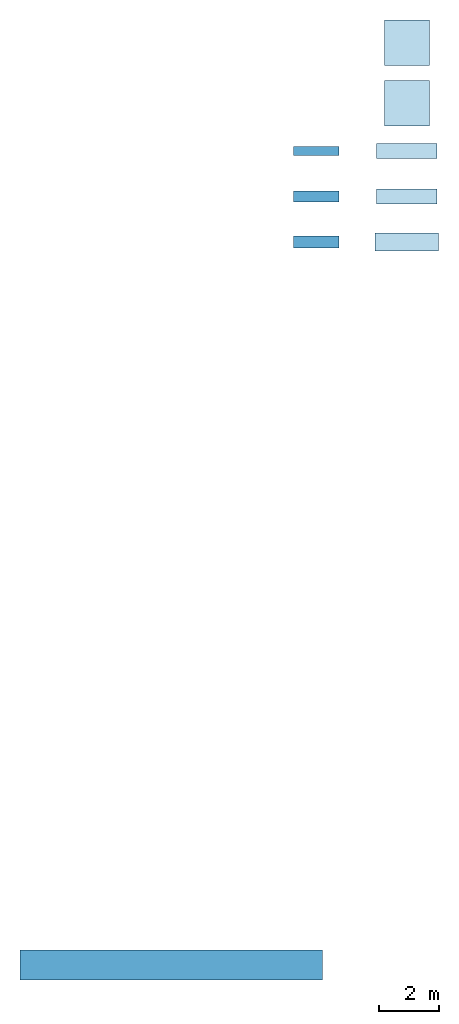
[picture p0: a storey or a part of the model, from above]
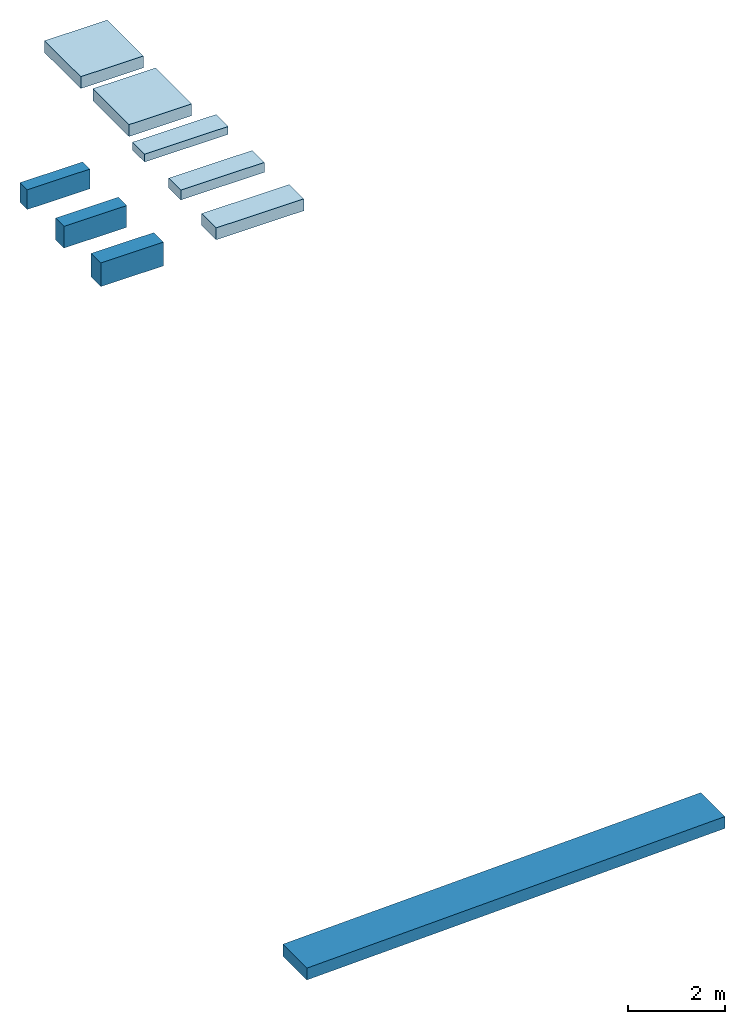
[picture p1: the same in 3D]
Properties of the parts of a building model (IFC2X3)

# File
Description: ViewDefinition [CoordinationView_V2.0]
Time: 2013-09-27T11:32:29
Written by: The EXPRESS Data Manager Version 5.01.0100.02.64mod : 6 Jun 2012
Made in: 20130308_1515(x64) - Exporter 3.5.0.0 - Alternate UI 2.5.0.0
Comment: STEP Physical File produced by: The EXPRESS Data Manager Version 5.01.0100.02.64mod : 6 Jun 2012 * Module: EDMstepFileFactory/EDMstandAlone * Creation date: Fri Sep 27 11:32:29 2013 * Host: MDR_LPTP_BTO * Database: C:\Users\Martijn\AppData\Local\Temp\{5681AB90-63A4-409C-9CCB-B684B3D83B4A}\ifc * Database version: 5507 * Database creation date: Fri Sep 27 11:31:57 2013 * Schema: IFC2X3 * Model: DataRepository.ifc * Model creation date: Fri Sep 27 11:31:58 2013 * Header model: DataRepository.ifc_HeaderModel * Header model creation date: Fri Sep 27 11:31:58 2013 * EDMuser: sdai-user * EDMgroup: sdai-group * License ID and type: 5605 : Permanent license. Expiry date: * EDMstepFileFactory options: 020000

# IfcProject
LongName: E:\MdR Advies\Google Drive\001 - Overige werkzaamheden\RTC\RTC2013 Session 6 - IFC for Interoperability\files\presentation files\example 1 - default export using DRS parameter mapping.ifc

# IfcSite, Surface:5707
RefLatitude: 52, 22, 59, 879998; RefLongitude: 4, 55, 0, 119998; RefElevation: 0 mm

# IfcBuilding
Pset_BuildingCommon - NumberOfStoreys: 8

# IfcBuildingStorey (3)
Name | LongName | Elevation (mm)
-01 kelder | -01 kelder | -3000
00_begane grond | 00_begane grond | 0
01_eerste verdieping | 01_eerste verdieping | 3000

# IfcBuildingElementProxy: 00_Mass_bestaand:229168 : 00_Mass_bestaand:00_Mass_bestaand:229168, 00_Mass_bestaand:00_Mass_bestaand:229168:00_Mass_bestaand:229168 : 00_Mass_bestaand:00_Mass_bestaand:229168:4787
In: 00_begane grond
Material: 000_MA_bestaande bebouwing_IP
Pset_BuildingElementProxyCommon - Reference: 00_Mass_bestaand

# IfcBuildingElementProxy: 45_CEI_plafond_MEP_host:55413 : Basic Ceiling:45_CEI_plafond_MEP_host:55413, Basic Ceiling:45_CEI_plafond_MEP_host:55413:45_CEI_plafond_MEP_host:55413 : Basic Ceiling:45_CEI_plafond_MEP_host:55413:2324
In: 00_begane grond
Pset_BuildingElementProxyCommon - Reference: 45_CEI_plafond_MEP_host

# IfcBuildingElementProxy: 45_CEI_plafond_gipsplaat_610mm_wit:58956 : Compound Ceiling:45_CEI_plafond_gipsplaat_610mm_wit:58956, Compound Ceiling:45_CEI_plafond_gipsplaat_610mm_wit:58956:45_CEI_plafond_gipsplaat_610mm_wit:58956 : Compound Ceiling:45_CEI_plafond_gipsplaat_610mm_wit:58956:2332
In: 00_begane grond
Material: 45_gips_plafond_beplating_610mm
Pset_BuildingElementProxyCommon - Reference: 45_CEI_plafond_gipsplaat_610mm_wit:58956 : Compound Ceiling:45_CEI_plafond_gipsplaat_610mm_wit:58956

# IfcBuildingElementProxy: 45_CEI_systeemplafond_1200x600_wit:59181 : Compound Ceiling:45_CEI_systeemplafond_1200x600_wit:59181, Compound Ceiling:45_CEI_systeemplafond_1200x600_wit:59181:45_CEI_systeemplafond_1200x600_wit:59181 : Compound Ceiling:45_CEI_systeemplafond_1200x600_wit:59181:2381
In: 00_begane grond
Material: 45_plafond_systeemplafond_1200x600_wit
Pset_BuildingElementProxyCommon - Reference: 45_CEI_systeemplafond_1200x600_wit

# IfcBuildingElementProxy: 45_CEI_systeemplafond_600x600_rood:59157 : Compound Ceiling:45_CEI_systeemplafond_600x600_rood:59157, Compound Ceiling:45_CEI_systeemplafond_600x600_rood:59157:45_CEI_systeemplafond_600x600_rood:59157 : Compound Ceiling:45_CEI_systeemplafond_600x600_rood:59157:2366
In: 00_begane grond
Material: 45_plafond_systeemplafond_600x600_donkerrood
Pset_BuildingElementProxyCommon - Reference: 45_CEI_systeemplafond_600x600_rood

# IfcBuildingElementProxy: 45_CEI_systeemplafond_600x600_wit:59123 : Compound Ceiling:45_CEI_systeemplafond_600x600_wit:59123, Compound Ceiling:45_CEI_systeemplafond_600x600_wit:59123:45_CEI_systeemplafond_600x600_wit:59123 : Compound Ceiling:45_CEI_systeemplafond_600x600_wit:59123:2347
In: 00_begane grond
Material: 45_plafond_systeemplafond_600x600_wit
Pset_BuildingElementProxyCommon - Reference: 45_CEI_systeemplafond_600x600_wit

# IfcFlowFitting: 61_CT_kabelgoot_open:180304 : Cable Tray with Fittings:61_CT_kabelgoot_open:180304, Cable Tray with Fittings:61_CT_kabelgoot_open:180304:61_CT_kabelgoot_open:180304 : Cable Tray with Fittings:61_CT_kabelgoot_open:180304:4527
In: 00_begane grond
Pset_DistributionFlowElementCommon - Reference: 61_CT_kabelgoot_open

# IfcFlowFitting: 61_CT_kabelgoot_open:206202 : Cable Tray without Fittings:61_CT_kabelgoot_open:206202, Cable Tray without Fittings:61_CT_kabelgoot_open:206202:61_CT_kabelgoot_open:206202 : Cable Tray without Fittings:61_CT_kabelgoot_open:206202:4714
In: 00_begane grond
Pset_DistributionFlowElementCommon - Reference: 61_CT_kabelgoot_open

# IfcFlowTerminal: aanvoer_plafondrooster_kanaaldiameter_250:221553 : 57_AT_plafondrooster_toev_rond_kanaal_FB:aanvoer_plafondrooster_kanaaldiameter_250:221553, 57_AT_plafondrooster_toev_rond_kanaal_FB:aanvoer_plafondrooster_kanaaldiameter_250:221553:aanvoer_plafondrooster_kanaaldiameter_250:221553 : 57_AT_plafondrooster_toev_rond_kanaal_FB:aanvoer_plafondrooster_kanaaldiameter_250:221553:2163
In: 00_begane grond
Pset_ManufacturerTypeInformation - Manufacturer: RevitGG

# IfcFlowTerminal: afvoer_plafondrooster_kanaaldiameter_250:124771 : 57_AT_plafondrooster_afv_rond_kanaal_FB:afvoer_plafondrooster_kanaaldiameter_250:124771, 57_AT_plafondrooster_afv_rond_kanaal_FB:afvoer_plafondrooster_kanaaldiameter_250:124771:afvoer_plafondrooster_kanaaldiameter_250:124771 : 57_AT_plafondrooster_afv_rond_kanaal_FB:afvoer_plafondrooster_kanaaldiameter_250:124771:2126
In: 00_begane grond
Pset_ManufacturerTypeInformation - Manufacturer: RevitGG

# IfcFlowTerminal: afvoer_rozet_kanaaldiameter_200:148100 : 57_AT_afv_rozet_FB:afvoer_rozet_kanaaldiameter_200:148100, 57_AT_afv_rozet_FB:afvoer_rozet_kanaaldiameter_200:148100:afvoer_rozet_kanaaldiameter_200:148100 : 57_AT_afv_rozet_FB:afvoer_rozet_kanaaldiameter_200:148100:2156
In: 00_begane grond
Pset_ManufacturerTypeInformation - Manufacturer: RevitGG

# IfcFooting: Foundation Slab:16_SFO_funderingsplaat_ihwg_beton_C30/37:68150:Foundation Slab:16_SFO_funderingsplaat_ihwg_beton_C30/37:68150, Foundation Slab:16_SFO_funderingsplaat_ihwg_beton_C30/37:68150:16_SFO_funderingsplaat_ihwg_beton_C30/37:68150 : Foundation Slab:16_SFO_funderingsplaat_ihwg_beton_C30/37:68150:2446
In: -01 kelder
Material: 16_beton_ihwg_C30/35

# IfcFooting: Wall Foundation:16_SFO_ihwg beton_C30-35_500x200:317217:Wall Foundation:16_SFO_ihwg beton_C30-35_500x200:317217, Wall Foundation:16_SFO_ihwg beton_C30-35_500x200:317217:16_SFO_ihwg beton_C30-35_500x200:317217 : Wall Foundation:16_SFO_ihwg beton_C30-35_500x200:317217:2189
In: -01 kelder
Material: 16_beton_ihwg_C30/35

# IfcFooting: Wall Foundation:16_SFO_ihwg beton_C30-35_500x250:317290:Wall Foundation:16_SFO_ihwg beton_C30-35_500x250:317290, Wall Foundation:16_SFO_ihwg beton_C30-35_500x250:317290:16_SFO_ihwg beton_C30-35_500x250:317290 : Wall Foundation:16_SFO_ihwg beton_C30-35_500x250:317290:2204
In: -01 kelder
Material: 16_beton_ihwg_C30/35

# IfcFooting: Wall Foundation:16_SFO_ihwg beton_C30-35_600x300:317374:Wall Foundation:16_SFO_ihwg beton_C30-35_600x300:317374, Wall Foundation:16_SFO_ihwg beton_C30-35_600x300:317374:16_SFO_ihwg beton_C30-35_600x300:317374 : Wall Foundation:16_SFO_ihwg beton_C30-35_600x300:317374:2218
In: -01 kelder
Material: 16_beton_ihwg_C30/35

# IfcFooting: Wall Foundation:16_SFO_prefab beton_C35-45_300x500:317420:Wall Foundation:16_SFO_prefab beton_C35-45_300x500:317420, Wall Foundation:16_SFO_prefab beton_C35-45_300x500:317420:16_SFO_prefab beton_C35-45_300x500:317420 : Wall Foundation:16_SFO_prefab beton_C35-45_300x500:317420:2232
In: -01 kelder
Material: 16_beton_prefab_C35-45

# IfcFooting: Wall Foundation:16_SFO_prefab beton_C35-45_350x550:317423:Wall Foundation:16_SFO_prefab beton_C35-45_350x550:317423, Wall Foundation:16_SFO_prefab beton_C35-45_350x550:317423:16_SFO_prefab beton_C35-45_350x550:317423 : Wall Foundation:16_SFO_prefab beton_C35-45_350x550:317423:2247
In: -01 kelder
Material: 16_beton_prefab_C35-45

# IfcFooting: Wall Foundation:16_SFO_prefab beton_C35-45_400x600:317426:Wall Foundation:16_SFO_prefab beton_C35-45_400x600:317426, Wall Foundation:16_SFO_prefab beton_C35-45_400x600:317426:16_SFO_prefab beton_C35-45_400x600:317426 : Wall Foundation:16_SFO_prefab beton_C35-45_400x600:317426:2261
In: -01 kelder
Material: 16_beton_prefab_C35-45

# IfcRamp: Ramp:24_RA_hellingbaan_beton_prefab_300:77835:1:Ramp:24_RA_hellingbaan_beton_prefab_300:77835:1:4334 (2)
In: -01 kelder
Name (Ramp:24_RA_hellingbaan_beton_prefab_300:77835:1:24_RA_hellingbaan_beton_prefab_300:77835:1 : Ramp:24_RA_hellingbaan_beton_prefab_300:77835:1:...)
4336 | Material: 24_beton_prefab_generiek
4336 | Pset_RampCommon - Reference: 24_RA_hellingbaan_beton_prefab_300:77835:1 : Ramp:24_RA_hellingbaan_beton_prefab_300:77835:1; IsExternal: no

# IfcRamp: Ramp:24_RA_hellingbaan_beton_prefab_solid:79050:1:Ramp:24_RA_hellingbaan_beton_prefab_solid:79050:1:4359 (2)
In: 00_begane grond
Name (Ramp:24_RA_hellingbaan_beton_prefab_solid:79050:1:24_RA_hellingbaan_beton_prefab_solid:79050:1 : Ramp:24_RA_hellingbaan_beton_prefab_solid:79050:1:...)
4361 | Material: 24_beton_prefab_generiek
4361 | Pset_RampCommon - Reference: 24_RA_hellingbaan_beton_prefab_solid:79050:1 : Ramp:24_RA_hellingbaan_beton_prefab_solid:79050:1; IsExternal: no

# IfcRoof: 27_CWP_SAB58KD_945:SAB58KD_945:165322:27_CWP_SAB58KD_945:SAB58KD_945:165322:4384, 27_CWP_SAB58KD_945:SAB58KD_945:165322:SAB58KD_945:165322 : 27_CWP_SAB58KD_945:SAB58KD_945:165322:4386
In: 00_begane grond
Material: Default Roof
Pset_RoofCommon - Reference: 27_CW_SAB58KD_945mm; IsExternal: yes

# IfcRoof: Basic Roof:27_RO_dakplaat_enkelschalig_PIR_135_33-90-12:69928:Basic Roof:27_RO_dakplaat_enkelschalig_PIR_135_33-90-12:69928:4278, Basic Roof:27_RO_dakplaat_enkelschalig_PIR_135_33-90-12:69928:27_RO_dakplaat_enkelschalig_PIR_135_33-90-12:69928 : Basic Roof:27_RO_dakplaat_enkelschalig_PIR_135_33-90-12:69928:4280
In: 00_begane grond
Material: Default Roof
Pset_RoofCommon - Reference: 27_RO_dakplaat_enkelschalig_PIR_135_33-90-12; IsExternal: yes

# IfcRoof: Basic Roof:27_RO_dakplaat_sandwich_PIR_106_20-3-80-3:77055:Basic Roof:27_RO_dakplaat_sandwich_PIR_106_20-3-80-3:77055:4320, Basic Roof:27_RO_dakplaat_sandwich_PIR_106_20-3-80-3:77055:27_RO_dakplaat_sandwich_PIR_106_20-3-80-3:77055 : Basic Roof:27_RO_dakplaat_sandwich_PIR_106_20-3-80-3:77055:4322
In: 00_begane grond
Material: Default Roof
Pset_RoofCommon - Reference: 27_RO_dakplaat_sandwich_PIR_106_20-3-80-3; IsExternal: yes

# IfcRoof: Basic Roof:27_RO_generiek_200:69710:Basic Roof:27_RO_generiek_200:69710:4203, Basic Roof:27_RO_generiek_200:69710:27_RO_generiek_200:69710 : Basic Roof:27_RO_generiek_200:69710:4205
In: 00_begane grond
Material: Default Roof
Pset_RoofCommon - Reference: 27_RO_generiek_200; IsExternal: yes

# IfcRoof: Basic Roof:27_RO_generiek_300:69826:Basic Roof:27_RO_generiek_300:69826:4220, Basic Roof:27_RO_generiek_300:69826:27_RO_generiek_300:69826 : Basic Roof:27_RO_generiek_300:69826:4222
In: 00_begane grond
Material: Default Roof
Pset_RoofCommon - Reference: 27_RO_generiek_300; IsExternal: yes

# IfcRoof: Basic Roof:27_RO_hout_underlayment_189_171-18:69921:Basic Roof:27_RO_hout_underlayment_189_171-18:69921:4264, Basic Roof:27_RO_hout_underlayment_189_171-18:69921:27_RO_hout_underlayment_189_171-18:69921 : Basic Roof:27_RO_hout_underlayment_189_171-18:69921:4266
In: 00_begane grond
Material: Default Roof
Pset_RoofCommon - Reference: 27_RO_hout_underlayment_189_171-18; IsExternal: yes

# IfcRoof: Basic Roof:47_RO_dakpan_grijs_300x300:69939:Basic Roof:47_RO_dakpan_grijs_300x300:69939:4292, Basic Roof:47_RO_dakpan_grijs_300x300:69939:47_RO_dakpan_grijs_300x300:69939 : Basic Roof:47_RO_dakpan_grijs_300x300:69939:4294
In: 00_begane grond
Material: Default Roof
Pset_RoofCommon - Reference: 47_RO_dakpan_grijs_300x300; IsExternal: yes

# IfcRoof: Basic Roof:47_RO_dakpan_rood_300x300:69946:Basic Roof:47_RO_dakpan_rood_300x300:69946:4306, Basic Roof:47_RO_dakpan_rood_300x300:69946:47_RO_dakpan_rood_300x300:69946 : Basic Roof:47_RO_dakpan_rood_300x300:69946:4308
In: 00_begane grond
Material: Default Roof
Pset_RoofCommon - Reference: 47_RO_dakpan_rood_300x300; IsExternal: yes

# IfcRoof: Basic Roof:47_RO_isolatie_EPS_bitumen_102_100-2:69892:Basic Roof:47_RO_isolatie_EPS_bitumen_102_100-2:69892:4250, Basic Roof:47_RO_isolatie_EPS_bitumen_102_100-2:69892:47_RO_isolatie_EPS_bitumen_102_100-2:69892 : Basic Roof:47_RO_isolatie_EPS_bitumen_102_100-2:69892:4252
In: 00_begane grond
Material: Default Roof
Pset_RoofCommon - Reference: 47_RO_isolatie_EPS_bitumen_102_100-2; IsExternal: yes

# IfcRoof: Basic Roof:47_RO_isolatie_PIR_bitumen_82_80-2:69885:Basic Roof:47_RO_isolatie_PIR_bitumen_82_80-2:69885:4234, Basic Roof:47_RO_isolatie_PIR_bitumen_82_80-2:69885:47_RO_isolatie_PIR_bitumen_82_80-2:69885 : Basic Roof:47_RO_isolatie_PIR_bitumen_82_80-2:69885:4236
In: 00_begane grond
Material: Default Roof
Pset_RoofCommon - Reference: 47_RO_isolatie_PIR_bitumen_82_80-2; IsExternal: yes

# IfcSlab: Basic Roof:27_RO_dakplaat_enkelschalig_PIR_135_33-90-12:69928:Basic Roof:27_RO_dakplaat_enkelschalig_PIR_135_33-90-12:69928:4278, Basic Roof:27_RO_dakplaat_enkelschalig_PIR_135_33-90-12:69928:27_RO_dakplaat_enkelschalig_PIR_135_33-90-12:69928 : Basic Roof:27_RO_dakplaat_enkelschalig_PIR_135_33-90-12:69928:4280:1
In: 00_begane grond
PredefinedType: ROOF; Material: Default Roof
Pset_SlabCommon - Reference: 27_RO_dakplaat_enkelschalig_PIR_135_33-90-12:69928 : Basic Roof:27_RO_dakplaat_enkelschalig_PIR_135_33-90-12:69928; IsExternal: yes; LoadBearing: yes; PitchAngle: 0 deg

# IfcSlab: Basic Roof:27_RO_dakplaat_sandwich_PIR_106_20-3-80-3:77055:Basic Roof:27_RO_dakplaat_sandwich_PIR_106_20-3-80-3:77055:4320, Basic Roof:27_RO_dakplaat_sandwich_PIR_106_20-3-80-3:77055:27_RO_dakplaat_sandwich_PIR_106_20-3-80-3:77055 : Basic Roof:27_RO_dakplaat_sandwich_PIR_106_20-3-80-3:77055:4322:1
In: 00_begane grond
PredefinedType: ROOF; Material: Default Roof
Pset_SlabCommon - Reference: 27_RO_dakplaat_sandwich_PIR_106_20-3-80-3:77055 : Basic Roof:27_RO_dakplaat_sandwich_PIR_106_20-3-80-3:77055; IsExternal: yes; LoadBearing: yes; PitchAngle: 0 deg

# IfcSlab: Basic Roof:27_RO_generiek_200:69710:Basic Roof:27_RO_generiek_200:69710:4203, Basic Roof:27_RO_generiek_200:69710:27_RO_generiek_200:69710 : Basic Roof:27_RO_generiek_200:69710:4205:1
In: 00_begane grond
PredefinedType: ROOF; Material: Default Roof
Pset_SlabCommon - Reference: 27_RO_generiek_200:69710 : Basic Roof:27_RO_generiek_200:69710; IsExternal: yes; LoadBearing: yes; PitchAngle: 0 deg

# IfcSlab: Basic Roof:27_RO_generiek_300:69826:Basic Roof:27_RO_generiek_300:69826:4220, Basic Roof:27_RO_generiek_300:69826:27_RO_generiek_300:69826 : Basic Roof:27_RO_generiek_300:69826:4222:1
In: 00_begane grond
PredefinedType: ROOF; Material: Default Roof
Pset_SlabCommon - Reference: 27_RO_generiek_300:69826 : Basic Roof:27_RO_generiek_300:69826; IsExternal: yes; LoadBearing: yes; PitchAngle: 0 deg

# IfcSlab: Basic Roof:27_RO_hout_underlayment_189_171-18:69921:Basic Roof:27_RO_hout_underlayment_189_171-18:69921:4264, Basic Roof:27_RO_hout_underlayment_189_171-18:69921:27_RO_hout_underlayment_189_171-18:69921 : Basic Roof:27_RO_hout_underlayment_189_171-18:69921:4266:1
In: 00_begane grond
PredefinedType: ROOF; Material: Default Roof
Pset_SlabCommon - Reference: 27_RO_hout_underlayment_189_171-18:69921 : Basic Roof:27_RO_hout_underlayment_189_171-18:69921; IsExternal: yes; LoadBearing: yes; PitchAngle: 0 deg

# IfcSlab: Basic Roof:47_RO_dakpan_grijs_300x300:69939:Basic Roof:47_RO_dakpan_grijs_300x300:69939:4292, Basic Roof:47_RO_dakpan_grijs_300x300:69939:47_RO_dakpan_grijs_300x300:69939 : Basic Roof:47_RO_dakpan_grijs_300x300:69939:4294:1
In: 00_begane grond
PredefinedType: ROOF; Material: Default Roof
Pset_SlabCommon - Reference: 47_RO_dakpan_grijs_300x300:69939 : Basic Roof:47_RO_dakpan_grijs_300x300:69939; IsExternal: yes; LoadBearing: yes; PitchAngle: 0 deg

# IfcSlab: Basic Roof:47_RO_dakpan_rood_300x300:69946:Basic Roof:47_RO_dakpan_rood_300x300:69946:4306, Basic Roof:47_RO_dakpan_rood_300x300:69946:47_RO_dakpan_rood_300x300:69946 : Basic Roof:47_RO_dakpan_rood_300x300:69946:4308:1
In: 00_begane grond
PredefinedType: ROOF; Material: Default Roof
Pset_SlabCommon - Reference: 47_RO_dakpan_rood_300x300:69946 : Basic Roof:47_RO_dakpan_rood_300x300:69946; IsExternal: yes; LoadBearing: yes; PitchAngle: 0 deg

# IfcSlab: Basic Roof:47_RO_isolatie_EPS_bitumen_102_100-2:69892:Basic Roof:47_RO_isolatie_EPS_bitumen_102_100-2:69892:4250, Basic Roof:47_RO_isolatie_EPS_bitumen_102_100-2:69892:47_RO_isolatie_EPS_bitumen_102_100-2:69892 : Basic Roof:47_RO_isolatie_EPS_bitumen_102_100-2:69892:4252:1
In: 00_begane grond
PredefinedType: ROOF; Material: Default Roof
Pset_SlabCommon - Reference: 47_RO_isolatie_EPS_bitumen_102_100-2:69892 : Basic Roof:47_RO_isolatie_EPS_bitumen_102_100-2:69892; IsExternal: yes; LoadBearing: yes; PitchAngle: 0 deg

# IfcSlab: Basic Roof:47_RO_isolatie_PIR_bitumen_82_80-2:69885:Basic Roof:47_RO_isolatie_PIR_bitumen_82_80-2:69885:4234, Basic Roof:47_RO_isolatie_PIR_bitumen_82_80-2:69885:47_RO_isolatie_PIR_bitumen_82_80-2:69885 : Basic Roof:47_RO_isolatie_PIR_bitumen_82_80-2:69885:4236:1
In: 00_begane grond
PredefinedType: ROOF; Material: Default Roof
Pset_SlabCommon - Reference: 47_RO_isolatie_PIR_bitumen_82_80-2:69885 : Basic Roof:47_RO_isolatie_PIR_bitumen_82_80-2:69885; IsExternal: yes; LoadBearing: yes; PitchAngle: 0 deg

# IfcSlab: Floor:Floor:11_FL_werkvloer_stampbeton_50, Floor:Floor:11_FL_werkvloer_stampbeton_50:5945
In: 00_begane grond
PredefinedType: FLOOR; Material: 11_werkvloer_stampbeton 50 mm
Pset_SlabCommon - Reference: Floor:11_FL_werkvloer_stampbeton_50; IsExternal: yes; LoadBearing: no; FireRating: 30; Combustible: yes; Compartmentation: yes; PitchAngle: 0 deg

# IfcSlab: Floor:Floor:13_FL_generiek_100, Floor:Floor:13_FL_generiek_100:5911
In: 00_begane grond
PredefinedType: FLOOR; Material: Default 100 mm
Pset_SlabCommon - Reference: Floor:13_FL_generiek_100; IsExternal: yes; LoadBearing: no; FireRating: 60; Combustible: no; Compartmentation: yes; PitchAngle: 0 deg

# IfcSlab: Floor:Floor:13_FL_ihwg_beton_geïsoleerd_222_120-100-2, Floor:Floor:13_FL_ihwg_beton_geïsoleerd_222_120-100-2:5953
In: 00_begane grond
PredefinedType: FLOOR; Material: 13_beton_ihwg_C20/25 120 mm, 20_isolatie_EPS 100 mm, 11_bodemafsluiter_folie 2 mm
Pset_SlabCommon - Reference: Floor:13_FL_ihwg_beton_geïsoleerd_222_120-100-2; IsExternal: yes; LoadBearing: no; FireRating: 60; Combustible: no; Compartmentation: yes; PitchAngle: 0 deg

# IfcSlab: Floor:Floor:23_FL_breedplaat_50, Floor:Floor:23_FL_breedplaat_50:5977
In: 00_begane grond
PredefinedType: FLOOR; Material: layer 50 mm
Pset_SlabCommon - Reference: Floor:23_FL_breedplaat_50; IsExternal: no; LoadBearing: no; FireRating: 90; Combustible: no; Compartmentation: yes; PitchAngle: 0 deg

# IfcSlab: Floor:Floor:23_FL_breedplaat_60, Floor:Floor:23_FL_breedplaat_60:5985
In: 00_begane grond
PredefinedType: FLOOR; Material: layer 60 mm
Pset_SlabCommon - Reference: Floor:23_FL_breedplaat_60; IsExternal: no; LoadBearing: no; Combustible: yes; Compartmentation: no; PitchAngle: 0 deg

# IfcSlab: Floor:Floor:23_FL_generiek_100, Floor:Floor:23_FL_generiek_100:5928
In: 00_begane grond
PredefinedType: FLOOR; Material: Default 100 mm
Pset_SlabCommon - Reference: Floor:23_FL_generiek_100; IsExternal: yes; LoadBearing: no; Combustible: no; Compartmentation: no; PitchAngle: 0 deg

# IfcSlab: Floor:Floor:23_FL_generiek_300, Floor:Floor:23_FL_generiek_300:5936
In: 00_begane grond
PredefinedType: FLOOR; Material: Default 300 mm
Pset_SlabCommon - Reference: Floor:23_FL_generiek_300; IsExternal: yes; LoadBearing: no; Combustible: no; Compartmentation: no; PitchAngle: 0 deg

# IfcSlab: Floor:Floor:23_FL_hout_underlayment_189mm_171-18, Floor:Floor:23_FL_hout_underlayment_189mm_171-18:6026
In: 00_begane grond
PredefinedType: FLOOR; Material: 23_beplating_underlayment 18 mm, 23_houten_balklaag_geventileerd 171 mm
Pset_SlabCommon - Reference: Floor:23_FL_hout_underlayment_189mm_171-18; IsExternal: no; LoadBearing: no; Combustible: no; Compartmentation: no; PitchAngle: 0 deg

# IfcSlab: Floor:Floor:23_FL_ihwg_beton_200, Floor:Floor:23_FL_ihwg_beton_200:5961
In: 00_begane grond
PredefinedType: FLOOR; Material: 13_beton_ihwg_C20/25 200 mm
Pset_SlabCommon - Reference: Floor:23_FL_ihwg_beton_200; IsExternal: no; LoadBearing: no; Combustible: no; Compartmentation: no; PitchAngle: 0 deg

# IfcSlab: Floor:Floor:23_FL_ihwg_beton_300, Floor:Floor:23_FL_ihwg_beton_300:5969
In: 00_begane grond
PredefinedType: FLOOR; Material: 13_beton_ihwg_C20/25 300 mm
Pset_SlabCommon - Reference: Floor:23_FL_ihwg_beton_300; IsExternal: no; LoadBearing: no; FireRating: 90; Combustible: no; Compartmentation: yes; PitchAngle: 0 deg

# IfcSlab: Floor:Floor:23_FL_kanaalplaat_200, Floor:Floor:23_FL_kanaalplaat_200:5993
In: 00_begane grond
PredefinedType: FLOOR; Material: layer 200 mm
Pset_SlabCommon - Reference: Floor:23_FL_kanaalplaat_200; IsExternal: no; LoadBearing: no; Combustible: no; Compartmentation: no; PitchAngle: 0 deg

# IfcSlab: Floor:Floor:23_FL_kanaalplaat_260, Floor:Floor:23_FL_kanaalplaat_260:6001
In: 00_begane grond
PredefinedType: FLOOR; Material: layer 260 mm
Pset_SlabCommon - Reference: Floor:23_FL_kanaalplaat_260; IsExternal: no; LoadBearing: no; Combustible: yes; Compartmentation: no; PitchAngle: 0 deg

# IfcSlab: Floor:Floor:23_FL_zwaluwstaartvloer_ihwg_beton_50, Floor:Floor:23_FL_zwaluwstaartvloer_ihwg_beton_50:6009
In: 00_begane grond
PredefinedType: FLOOR; Material: 13_beton_ihwg_C20/25 50 mm
Pset_SlabCommon - Reference: Floor:23_FL_zwaluwstaartvloer_ihwg_beton_50; IsExternal: no; LoadBearing: no; Combustible: no; Compartmentation: no; PitchAngle: 0 deg

# IfcSlab: Floor:Floor:23_FL_zwaluwstaartvloer_ihwg_beton_75, Floor:Floor:23_FL_zwaluwstaartvloer_ihwg_beton_75:6017
In: 00_begane grond
PredefinedType: FLOOR; Material: 13_beton_ihwg_C20/25 75 mm
Pset_SlabCommon - Reference: Floor:23_FL_zwaluwstaartvloer_ihwg_beton_75; IsExternal: no; LoadBearing: no; Combustible: no; Compartmentation: no; PitchAngle: 0 deg

# IfcSlab: Floor:Floor:43_FL_cementdekvloer_50, Floor:Floor:43_FL_cementdekvloer_50:6034
In: 00_begane grond
PredefinedType: FLOOR; Material: 43_dekvloer_zandcement 50 mm
Pset_SlabCommon - Reference: Floor:43_FL_cementdekvloer_50; IsExternal: no; LoadBearing: no; Combustible: no; Compartmentation: no; PitchAngle: 0 deg

# IfcSlab: Floor:Floor:43_FL_cementdekvloer_70, Floor:Floor:43_FL_cementdekvloer_70:6042
In: 00_begane grond
PredefinedType: FLOOR; Material: 43_dekvloer_zandcement 70 mm
Pset_SlabCommon - Reference: Floor:43_FL_cementdekvloer_70; IsExternal: no; LoadBearing: no; Combustible: no; Compartmentation: no; PitchAngle: 0 deg

# IfcSlab: Floor:Floor:43_FL_eiken_planken 150_geluidsisolatie_52_22-30, Floor:Floor:43_FL_eiken_planken 150_geluidsisolatie_52_22-30:6051
In: 00_begane grond
PredefinedType: FLOOR; Material: 43_vloerafwerking_hout_planken 22 mm, 20_isolatie_steenwol 30 mm
Pset_SlabCommon - Reference: Floor:43_FL_eiken_planken 150_geluidsisolatie_52_22-30; IsExternal: no; LoadBearing: no; Combustible: no; Compartmentation: no; PitchAngle: 0 deg

# IfcSlab: Floor:Floor:43_FL_tapijt_rood, Floor:Floor:43_FL_tapijt_rood:6059
In: 00_begane grond
PredefinedType: FLOOR; Material: 43_tapijt_rood 9 mm
Pset_SlabCommon - Reference: Floor:43_FL_tapijt_rood; IsExternal: no; LoadBearing: no; Combustible: no; Compartmentation: no; PitchAngle: 0 deg

# IfcSlab: Floor:Pad:90_SITE_bouwplaats, Floor:Pad:90_SITE_bouwplaats:6081
In: 00_begane grond
PredefinedType: FLOOR; Material: 90_bouwplaats 300 mm
Pset_SlabCommon - Reference: Pad:90_SITE_bouwplaats; IsExternal: no; LoadBearing: no; PitchAngle: 0 deg

# IfcStair: Assembled Stair:Stair:68679 Run 1:Assembled Stair:Stair:68679 Run 1:2493 (2)
In: 00_begane grond
Name (Assembled Stair:Stair:68679 Run 1:Stair:68679 Run 1 : Assembled Stair:Stair:68679 Run 1:...)
2495
2495 | Pset_StairCommon - Reference: 24_STR_trede_hout_vuren_40_neus_50_stootbord_10; IsExternal: no; NumberOfTreads: 16; TreadLength: 67056 mm

# IfcStair: Assembled Stair:Stair:68679 Stringer 1:Assembled Stair:Stair:68679 Stringer 1:2458 (2)
In: 00_begane grond
Name (Assembled Stair:Stair:68679 Stringer 1:Stair:68679 Stringer 1 : Assembled Stair:Stair:68679 Stringer 1:...)
2460
2460 | Pset_StairCommon - Reference: 24_ST_houten trap_gesloten_b=850_op=185_aan=220; IsExternal: no; NumberOfTreads: 0

# IfcStair: Assembled Stair:Stair:68953 Run 1:Assembled Stair:Stair:68953 Run 1:2779 (2)
In: 00_begane grond
Name (Assembled Stair:Stair:68953 Run 1:Stair:68953 Run 1 : Assembled Stair:Stair:68953 Run 1:...)
2781
2781 | Pset_StairCommon - Reference: 24_STR_trede_hout_vuren_40_neus_50; IsExternal: no; NumberOfTreads: 16; TreadLength: 20438669 mm

# IfcStair: Assembled Stair:Stair:68953 Stringer 1:Assembled Stair:Stair:68953 Stringer 1:2754 (2)
In: 00_begane grond
Name (Assembled Stair:Stair:68953 Stringer 1:Stair:68953 Stringer 1 : Assembled Stair:Stair:68953 Stringer 1:...)
2756
2756 | Pset_StairCommon - Reference: 24_ST_houten trap_open_b=850_op=185_aan=220; IsExternal: no; NumberOfTreads: 0

# IfcStair: Assembled Stair:Stair:69257 Run 1:Assembled Stair:Stair:69257 Run 1:2987 (2)
In: 00_begane grond
Name (Assembled Stair:Stair:69257 Run 1:Stair:69257 Run 1 : Assembled Stair:Stair:69257 Run 1:...)
2989
2989 | Pset_StairCommon - Reference: 24_STR_trede_hout_vuren_40_neus_50; IsExternal: no; NumberOfTreads: 16; TreadLength: 20438669 mm

# IfcStair: Assembled Stair:Stair:69257 Stringer 1:Assembled Stair:Stair:69257 Stringer 1:2902 (2)
In: 00_begane grond
Name (Assembled Stair:Stair:69257 Stringer 1:Stair:69257 Stringer 1 : Assembled Stair:Stair:69257 Stringer 1:...)
2904
2904 | Pset_StairCommon - Reference: 24_ST_houten trap_open_gezadeld_b=850_op=185_aan=220; IsExternal: no; NumberOfTreads: 0

# IfcStair: Assembled Stair:Stair:69261 Run 1:Assembled Stair:Stair:69261 Run 1:3155 (2)
In: 00_begane grond
Name (Assembled Stair:Stair:69261 Run 1:Stair:69261 Run 1 : Assembled Stair:Stair:69261 Run 1:...)
3157
3157 | Pset_StairCommon - Reference: 24_STR_trede_hout_vuren_40_neus_50; IsExternal: no; NumberOfTreads: 16; TreadLength: 20438669 mm

# IfcStair: Assembled Stair:Stair:69261 Stringer 1:Assembled Stair:Stair:69261 Stringer 1:3110 (2)
In: 00_begane grond
Name (Assembled Stair:Stair:69261 Stringer 1:Stair:69261 Stringer 1 : Assembled Stair:Stair:69261 Stringer 1:...)
3112
3112 | Pset_StairCommon - Reference: 24_ST_houten trap_open_middenboom_b=850_op=185_aan=220; IsExternal: no; NumberOfTreads: 0

# IfcStair: Assembled Stair:Stair:69280 Run 1:Assembled Stair:Stair:69280 Run 1:3303 (2)
In: 00_begane grond
Name (Assembled Stair:Stair:69280 Run 1:Stair:69280 Run 1 : Assembled Stair:Stair:69280 Run 1:...)
3305 | Material: 24_staal_gegalvaniseerd_rooster_generiek
3305 | Pset_StairCommon - Reference: 24_STR_trede_staal_gegalvaniseerd_rooster_15_neus_50_stootbord_15; IsExternal: no; NumberOfTreads: 16; TreadLength: 20438669 mm

# IfcStair: Assembled Stair:Stair:69280 Stringer 1:Assembled Stair:Stair:69280 Stringer 1:3278 (2)
In: 00_begane grond
Name (Assembled Stair:Stair:69280 Stringer 1:Stair:69280 Stringer 1 : Assembled Stair:Stair:69280 Stringer 1:...)
3280
3280 | Pset_StairCommon - Reference: 24_ST_stalen trap_gesloten_b=1000_op=185_aan=220; IsExternal: no; NumberOfTreads: 0

# IfcStair: Assembled Stair:Stair:69283 Run 1:Assembled Stair:Stair:69283 Run 1:3571 (2)
In: 00_begane grond
Name (Assembled Stair:Stair:69283 Run 1:Stair:69283 Run 1 : Assembled Stair:Stair:69283 Run 1:...)
3573 | Material: 24_staal_gegalvaniseerd_rooster_generiek
3573 | Pset_StairCommon - Reference: 24_STR_trede_staal_gegalvaniseerd_rooster_15_neus_50; IsExternal: no; NumberOfTreads: 16; TreadLength: 20438669 mm

# IfcStair: Assembled Stair:Stair:69283 Stringer 1:Assembled Stair:Stair:69283 Stringer 1:3546 (2)
In: 00_begane grond
Name (Assembled Stair:Stair:69283 Stringer 1:Stair:69283 Stringer 1 : Assembled Stair:Stair:69283 Stringer 1:...)
3548
3548 | Pset_StairCommon - Reference: 24_ST_stalen trap_open_b=850_op=185_aan=150; IsExternal: no; NumberOfTreads: 0

# IfcStair: Assembled Stair:Stair:69288 Run 1:Assembled Stair:Stair:69288 Run 1:3719 (2)
In: 00_begane grond
Name (Assembled Stair:Stair:69288 Run 1:Stair:69288 Run 1 : Assembled Stair:Stair:69288 Run 1:...)
3721 | Material: 24_staal_gegalvaniseerd_rooster_generiek
3721 | Pset_StairCommon - Reference: 24_STR_trede_staal_gegalvaniseerd_rooster_15_neus_50; IsExternal: no; NumberOfTreads: 16; TreadLength: 20438669 mm

# IfcStair: Assembled Stair:Stair:69288 Stringer 1:Assembled Stair:Stair:69288 Stringer 1:3694 (2)
In: 00_begane grond
Name (Assembled Stair:Stair:69288 Stringer 1:Stair:69288 Stringer 1 : Assembled Stair:Stair:69288 Stringer 1:...)
3696
3696 | Pset_StairCommon - Reference: 24_ST_stalen trap_open_b=850_op=185_aan=220; IsExternal: no; NumberOfTreads: 0

# IfcStair: Assembled Stair:Stair:69305 Run 1:Assembled Stair:Stair:69305 Run 1:3867 (2)
In: 00_begane grond
Name (Assembled Stair:Stair:69305 Run 1:Stair:69305 Run 1 : Assembled Stair:Stair:69305 Run 1:...)
3869 | Material: 24_staal_gegalvaniseerd_rooster_generiek
3869 | Pset_StairCommon - Reference: 24_STR_trede_staal_gegalvaniseerd_rooster_15_neus_50; IsExternal: no; NumberOfTreads: 16; TreadLength: 20438669 mm

# IfcStair: Assembled Stair:Stair:69305 Stringer 1:Assembled Stair:Stair:69305 Stringer 1:3842 (2)
In: 00_begane grond
Name (Assembled Stair:Stair:69305 Stringer 1:Stair:69305 Stringer 1 : Assembled Stair:Stair:69305 Stringer 1:...)
3844
3844 | Pset_StairCommon - Reference: 24_ST_stalen trap_open_b=1000_op=185_aan=350; IsExternal: no; NumberOfTreads: 0

# IfcStair: Assembled Stair:Stair:69309 Run 1:Assembled Stair:Stair:69309 Run 1:4035 (2)
In: 00_begane grond
Name (Assembled Stair:Stair:69309 Run 1:Stair:69309 Run 1 : Assembled Stair:Stair:69309 Run 1:...)
4037 | Material: 24_staal_gegalvaniseerd_rooster_generiek
4037 | Pset_StairCommon - Reference: 24_STR_trede_staal_gegalvaniseerd_rooster_15_neus_50; IsExternal: no; NumberOfTreads: 16; TreadLength: 20438669 mm

# IfcStair: Assembled Stair:Stair:69309 Stringer 1:Assembled Stair:Stair:69309 Stringer 1:3990 (2)
In: 00_begane grond
Name (Assembled Stair:Stair:69309 Stringer 1:Stair:69309 Stringer 1 : Assembled Stair:Stair:69309 Stringer 1:...)
3992
3992 | Pset_StairCommon - Reference: 24_ST_stalen trap_open_middenboom_b=1000_op=185_aan=220; IsExternal: no; NumberOfTreads: 0

# IfcStair: Cast-In-Place Stair:Stair:69314 Run 1:Cast-In-Place Stair:Stair:69314 Run 1:4158 (2)
In: 00_begane grond
Name (Cast-In-Place Stair:Stair:69314 Run 1:Stair:69314 Run 1 : Cast-In-Place Stair:Stair:69314 Run 1:...)
4160 | Material: 24_beton_prefab_generiek
4160 | Pset_StairCommon - Reference: 24_STR_trap_beton_prefab_50_50_50; IsExternal: no; NumberOfTreads: 16; TreadLength: 20438669 mm

# IfcStair: Cast-In-Place Stair:Stair:69318 Run 1:Cast-In-Place Stair:Stair:69318 Run 1:4170 (2)
In: 00_begane grond
Name (Cast-In-Place Stair:Stair:69318 Run 1:Stair:69318 Run 1 : Cast-In-Place Stair:Stair:69318 Run 1:...)
4172 | Material: 24_beton_prefab_generiek
4172 | Pset_StairCommon - Reference: 24_STR_trap_beton_prefab_monolithisch_recht; IsExternal: no; NumberOfTreads: 16; TreadLength: 20438669 mm

# IfcStair: Precast Stair:Stair:69323 Run 1:Precast Stair:Stair:69323 Run 1:4181 (2)
In: 00_begane grond
Name (Precast Stair:Stair:69323 Run 1:Stair:69323 Run 1 : Precast Stair:Stair:69323 Run 1:...)
4183 | Material: 24_beton_prefab_generiek
4183 | Pset_StairCommon - Reference: 24_STR_trap_beton_prefab_monolithisch_recht; IsExternal: no; NumberOfTreads: 16; TreadLength: 20438669 mm

# IfcStair: Precast Stair:Stair:69326 Run 1:Precast Stair:Stair:69326 Run 1:4192 (2)
In: 00_begane grond
Name (Precast Stair:Stair:69326 Run 1:Stair:69326 Run 1 : Precast Stair:Stair:69326 Run 1:...)
4194 | Material: 24_beton_prefab_generiek
4194 | Pset_StairCommon - Reference: 24_STR_trap_beton_prefab_50_50_50; IsExternal: no; NumberOfTreads: 16; TreadLength: 20438669 mm

# IfcWall: Curtain Wall:21_CW_binnendoos_SAB90_500:160824:21_CW_binnendoos_SAB90_500:160824 : Curtain Wall:21_CW_binnendoos_SAB90_500:160824, Curtain Wall:21_CW_binnendoos_SAB90_500:160824:21_CW_binnendoos_SAB90_500:160824 : Curtain Wall:21_CW_binnendoos_SAB90_500:160824:6090
In: 00_begane grond
Pset_WallCommon - Reference: 21_CW_binnendoos_SAB90_500:160824 : Curtain Wall:21_CW_binnendoos_SAB90_500:160824; LoadBearing: no; ExtendToStructure: no; IsExternal: no

# IfcWall: Curtain Wall:21_CW_gevelbeplating_SAB35_1035:60482:21_CW_gevelbeplating_SAB35_1035:60482 : Curtain Wall:21_CW_gevelbeplating_SAB35_1035:60482, Curtain Wall:21_CW_gevelbeplating_SAB35_1035:60482:21_CW_gevelbeplating_SAB35_1035:60482 : Curtain Wall:21_CW_gevelbeplating_SAB35_1035:60482:5924
In: 00_begane grond
Pset_WallCommon - Reference: 21_CW_gevelbeplating_SAB35_1035:60482 : Curtain Wall:21_CW_gevelbeplating_SAB35_1035:60482; LoadBearing: no; ExtendToStructure: no; IsExternal: no

# IfcWallStandardCase: Basic Wall:Basic Wall:20_WA_wand_generiek_100 (7)
In: 00_begane grond
Type - PredefinedType: STANDARD; Material: Default 100 mm
Pset_WallCommon - Reference: Basic Wall:20_WA_wand_generiek_100; LoadBearing: no; ExtendToStructure: no; IsExternal: yes; Combustible: yes; Compartmentation: no
PSet_COBIE - NominalWidth: 100
Name (Basic Wall:Basic Wall:20_WA_wand_generiek_100:...) | NominalLength
5875 | 2000
6094 | 1500
6095 | 1500
6096 | 1500
6097 | 1500
6098 | 1500
6099 | 1500

# IfcWallStandardCase: Basic Wall:Basic Wall:20_WA_wand_generiek_200, Basic Wall:Basic Wall:20_WA_wand_generiek_200:5876
In: 00_begane grond
Type - PredefinedType: STANDARD; Material: Default 200 mm
Pset_WallCommon - Reference: Basic Wall:20_WA_wand_generiek_200; LoadBearing: yes; ExtendToStructure: no; IsExternal: yes; Combustible: no; Compartmentation: no
PSet_COBIE - NominalLength: 2000; NominalWidth: 200

# IfcWallStandardCase: Basic Wall:Basic Wall:20_WA_wand_generiek_300, Basic Wall:Basic Wall:20_WA_wand_generiek_300:5877
In: 00_begane grond
Type - PredefinedType: STANDARD; Material: Default 300 mm
Pset_WallCommon - Reference: Basic Wall:20_WA_wand_generiek_300; LoadBearing: yes; ExtendToStructure: no; IsExternal: yes; Combustible: no; Compartmentation: no
PSet_COBIE - NominalLength: 2000; NominalWidth: 300

# IfcWallStandardCase: Basic Wall:Basic Wall:21_WA_hout-wrc-hor_rachel_tengel_iso-sw_180_20-30-10-120, Basic Wall:Basic Wall:21_WA_hout-wrc-hor_rachel_tengel_iso-sw_180_20-30-10-120:5888
In: 00_begane grond
Type - PredefinedType: STANDARD; Material: 41_hout_hardhout_geveldelen_donkerblauw_horizontaal 20 mm, 40_regelwerk_geventileerd 30 mm, 40_regelwerk_geventileerd 10 mm, 20_isolatie_steenwol 120 mm
Pset_WallCommon - Reference: Basic Wall:21_WA_hout-wrc-hor_rachel_tengel_iso-sw_180_20-30-10-120; LoadBearing: no; ExtendToStructure: no; IsExternal: yes; ThermalTransmittance: 0.274174 kg/K/s3; Combustible: no; Compartmentation: no
PSet_COBIE - NominalLength: 2000; NominalWidth: 180

# IfcWallStandardCase: Basic Wall:Basic Wall:21_WA_mw-bestaand_100, Basic Wall:Basic Wall:21_WA_mw-bestaand_100:5881
In: 00_begane grond
Type - PredefinedType: STANDARD; Material: 00_baksteen_bestaand 100 mm
Pset_WallCommon - Reference: Basic Wall:21_WA_mw-bestaand_100; LoadBearing: no; ExtendToStructure: no; IsExternal: yes; ThermalTransmittance: 4.1 kg/K/s3; Combustible: no; Compartmentation: no
PSet_COBIE - NominalLength: 2000; NominalWidth: 100

# IfcWallStandardCase: Basic Wall:Basic Wall:21_WA_mw-bestaand_spouw_mw-bestaand_300_100-100-100, Basic Wall:Basic Wall:21_WA_mw-bestaand_spouw_mw-bestaand_300_100-100-100:5883
In: 00_begane grond
Type - PredefinedType: STANDARD; Material: 00_baksteen_bestaand 100 mm, 00_lucht_spouw_muur_geventileerd 100 mm, 00_baksteen_bestaand 100 mm
Pset_WallCommon - Reference: Basic Wall:21_WA_mw-bestaand_spouw_mw-bestaand_300_100-100-100; LoadBearing: yes; ExtendToStructure: no; IsExternal: yes; ThermalTransmittance: 1.98096 kg/K/s3; Combustible: no; Compartmentation: no
PSet_COBIE - NominalLength: 2000; NominalWidth: 300

# IfcWallStandardCase: Basic Wall:Basic Wall:21_WA_mw_100, Basic Wall:Basic Wall:21_WA_mw_100:5878
In: 00_begane grond
Type - PredefinedType: STANDARD; Material: 20_baksteen_wf_210x100x50_10mm_voeg_halfsteens_rood_genuanceerd 100 mm
Pset_WallCommon - Reference: Basic Wall:21_WA_mw_100; LoadBearing: no; ExtendToStructure: no; IsExternal: yes; ThermalTransmittance: 4.1 kg/K/s3; Combustible: no; Compartmentation: no
PSet_COBIE - NominalLength: 2000; NominalWidth: 100

# IfcWallStandardCase: Basic Wall:Basic Wall:21_WA_mw_210, Basic Wall:Basic Wall:21_WA_mw_210:5879
In: 00_begane grond
Type - PredefinedType: STANDARD; Material: 20_baksteen_wf_210x100x50_10mm_voeg_halfsteens_rood_genuanceerd 210 mm
Pset_WallCommon - Reference: Basic Wall:21_WA_mw_210; LoadBearing: yes; ExtendToStructure: no; IsExternal: yes; ThermalTransmittance: 1.95238 kg/K/s3; Combustible: no; Compartmentation: no
PSet_COBIE - NominalLength: 2000; NominalWidth: 210

# IfcWallStandardCase: Basic Wall:Basic Wall:21_WA_mw_bestaand_210, Basic Wall:Basic Wall:21_WA_mw_bestaand_210:5882
In: 00_begane grond
Type - PredefinedType: STANDARD; Material: 00_baksteen_bestaand 210 mm
Pset_WallCommon - Reference: Basic Wall:21_WA_mw_bestaand_210; LoadBearing: yes; ExtendToStructure: no; IsExternal: yes; ThermalTransmittance: 1.95238 kg/K/s3; Combustible: no; Compartmentation: no
PSet_COBIE - NominalLength: 2000; NominalWidth: 210

# IfcWallStandardCase: Basic Wall:Basic Wall:21_WA_mw_spouw_170_100-70, Basic Wall:Basic Wall:21_WA_mw_spouw_170_100-70:5884
In: 00_begane grond
Type - PredefinedType: STANDARD; Material: 20_baksteen_wf_210x100x50_10mm_voeg_halfsteens_rood_genuanceerd 100 mm, 00_lucht_spouw_muur_geventileerd 70 mm
Pset_WallCommon - Reference: Basic Wall:21_WA_mw_spouw_170_100-70; LoadBearing: no; ExtendToStructure: no; IsExternal: yes; ThermalTransmittance: 3.90927 kg/K/s3; Combustible: no; Compartmentation: no
PSet_COBIE - NominalLength: 2000; NominalWidth: 170

# IfcWallStandardCase: Basic Wall:Basic Wall:21_WA_mw_spouw_iso-sw_170_100-20-50, Basic Wall:Basic Wall:21_WA_mw_spouw_iso-sw_170_100-20-50:5885
In: 00_begane grond
Type - PredefinedType: STANDARD; Material: 20_baksteen_wf_210x100x50_10mm_voeg_halfsteens_rood_genuanceerd 100 mm, 00_lucht_spouw_muur_geventileerd 20 mm, 20_isolatie_steenwol 50 mm
Pset_WallCommon - Reference: Basic Wall:21_WA_mw_spouw_iso-sw_170_100-20-50; LoadBearing: no; ExtendToStructure: no; IsExternal: yes; ThermalTransmittance: 0.582109 kg/K/s3; Combustible: no; Compartmentation: no
PSet_COBIE - NominalLength: 2000; NominalWidth: 170

# IfcWallStandardCase: Basic Wall:Basic Wall:21_WA_mw_spouw_iso-sw_200_100-30-70 (2)
In: 00_begane grond
Type - PredefinedType: STANDARD; Material: 20_baksteen_wf_210x100x50_10mm_voeg_halfsteens_rood_genuanceerd 100 mm, 00_lucht_spouw_muur_geventileerd 30 mm, 20_isolatie_steenwol 70 mm
Pset_WallCommon - Reference: Basic Wall:21_WA_mw_spouw_iso-sw_200_100-30-70; LoadBearing: no; ExtendToStructure: no; IsExternal: yes; ThermalTransmittance: 0.433308 kg/K/s3; Combustible: no; Compartmentation: no
PSet_COBIE - NominalLength: 2000; NominalWidth: 200
Name (Basic Wall:Basic Wall:21_WA_mw_spouw_iso-sw_200_100-30-70:...)
5886
5887

# IfcWallStandardCase: Basic Wall:Basic Wall:21_WA_mw_spouw_mw_300_100-100-100, Basic Wall:Basic Wall:21_WA_mw_spouw_mw_300_100-100-100:5880
In: 00_begane grond
Type - PredefinedType: STANDARD; Material: 20_baksteen_wf_210x100x50_10mm_voeg_halfsteens_rood_genuanceerd 100 mm, 00_lucht_spouw_muur_geventileerd 100 mm, 20_baksteen_wf_210x100x50_10mm_voeg_halfsteens_rood_genuanceerd 100 mm
Pset_WallCommon - Reference: Basic Wall:21_WA_mw_spouw_mw_300_100-100-100; LoadBearing: yes; ExtendToStructure: no; IsExternal: yes; ThermalTransmittance: 1.98096 kg/K/s3; Combustible: no; Compartmentation: no
PSet_COBIE - NominalLength: 2000; NominalWidth: 300

# IfcWallStandardCase: Basic Wall:Basic Wall:21_WA_sandwichpaneel_100x1000, Basic Wall:Basic Wall:21_WA_sandwichpaneel_100x1000:5891
In: 00_begane grond
Type - PredefinedType: STANDARD; Material: 41_staal_geanodizeerd_wit 1.6 mm, 20_isolatie_PIR 96.8 mm, 41_staal_geanodizeerd_wit 1.6 mm
Pset_WallCommon - Reference: Basic Wall:21_WA_sandwichpaneel_100x1000; LoadBearing: no; ExtendToStructure: no; IsExternal: yes; ThermalTransmittance: 0.309911 kg/K/s3; Combustible: no; Compartmentation: no
PSet_COBIE - NominalLength: 2000; NominalWidth: 100

# IfcWallStandardCase: Basic Wall:Basic Wall:21_WA_spouw_iso-sw_140_40-100, Basic Wall:Basic Wall:21_WA_spouw_iso-sw_140_40-100:6091
In: 00_begane grond
Type - PredefinedType: STANDARD; Material: 00_lucht_spouw_muur_geventileerd 40 mm, 20_isolatie_steenwol 100 mm
Pset_WallCommon - Reference: Basic Wall:21_WA_spouw_iso-sw_140_40-100; LoadBearing: no; ExtendToStructure: no; IsExternal: yes; ThermalTransmittance: 0.339216 kg/K/s3; Combustible: no; Compartmentation: no
PSet_COBIE - NominalLength: 2000; NominalWidth: 140

# IfcWallStandardCase: Basic Wall:Basic Wall:21_WA_stucwerk_iso-eps_150_30-120, Basic Wall:Basic Wall:21_WA_stucwerk_iso-eps_150_30-120:5890
In: 00_begane grond
Type - PredefinedType: STANDARD; Material: 40_stucwerk_exterieur_grof_wit 30 mm, 20_isolatie_EPS 120 mm
Pset_WallCommon - Reference: Basic Wall:21_WA_stucwerk_iso-eps_150_30-120; LoadBearing: no; ExtendToStructure: no; IsExternal: yes; ThermalTransmittance: 0.286747 kg/K/s3; Combustible: no; Compartmentation: no
PSet_COBIE - NominalLength: 2000; NominalWidth: 150

# IfcWallStandardCase: Basic Wall:Basic Wall:22_WA_cb_G2/400_100, Basic Wall:Basic Wall:22_WA_cb_G2/400_100:5898
In: 00_begane grond
Type - PredefinedType: STANDARD; Material: 22_cellenbeton G2/400 100 mm
Pset_WallCommon - Reference: Basic Wall:22_WA_cb_G2/400_100; LoadBearing: no; ExtendToStructure: no; IsExternal: no; ThermalTransmittance: 1.2 kg/K/s3; Combustible: no; Compartmentation: no
PSet_COBIE - NominalLength: 2000; NominalWidth: 100

# IfcWallStandardCase: Basic Wall:Basic Wall:22_WA_glazen_bouwsteen_80, Basic Wall:Basic Wall:22_WA_glazen_bouwsteen_80:5900
In: 00_begane grond
Type - PredefinedType: STANDARD; Material: 22_glazen_bouwsteen 80 mm
Pset_WallCommon - Reference: Basic Wall:22_WA_glazen_bouwsteen_80; LoadBearing: no; ExtendToStructure: no; IsExternal: no; ThermalTransmittance: 2.81125 kg/K/s3; Combustible: no; Compartmentation: no
PSet_COBIE - NominalLength: 2000; NominalWidth: 80

# IfcWallStandardCase: Basic Wall:Basic Wall:22_WA_kzs_CS12_100, Basic Wall:Basic Wall:22_WA_kzs_CS12_100:5897
In: 00_begane grond
Type - PredefinedType: STANDARD; Material: 22_kalkzandsteen_CS12 100 mm
Pset_WallCommon - Reference: Basic Wall:22_WA_kzs_CS12_100; LoadBearing: no; ExtendToStructure: no; IsExternal: no; ThermalTransmittance: 8.6 kg/K/s3; Combustible: no; Compartmentation: no
PSet_COBIE - NominalLength: 2000; NominalWidth: 100

# IfcWallStandardCase: Basic Wall:Basic Wall:22_WA_ms-wand_gips_isolatie_gips_95_12.5-70-12.5, Basic Wall:Basic Wall:22_WA_ms-wand_gips_isolatie_gips_95_12.5-70-12.5:5899
In: 00_begane grond
Type - PredefinedType: STANDARD; Material: 22_gips_beplating_wand_610mm 12.5 mm, 20_isolatie_steenwol 70 mm, 22_gips_beplating_wand_610mm 12.5 mm
Pset_WallCommon - Reference: Basic Wall:22_WA_ms-wand_gips_isolatie_gips_95_12.5-70-12.5; LoadBearing: no; ExtendToStructure: no; IsExternal: no; ThermalTransmittance: 0.476807 kg/K/s3; Combustible: no; Compartmentation: no
PSet_COBIE - NominalLength: 2000; NominalWidth: 95

# IfcWallStandardCase: Basic Wall:Basic Wall:28_WA_cb_G4/600_100, Basic Wall:Basic Wall:28_WA_cb_G4/600_100:5895
In: 00_begane grond
Type - PredefinedType: STANDARD; Material: 28_cellenbeton_G4/600 100 mm
Pset_WallCommon - Reference: Basic Wall:28_WA_cb_G4/600_100; LoadBearing: yes; ExtendToStructure: no; IsExternal: yes; ThermalTransmittance: 1.6 kg/K/s3; Combustible: no; Compartmentation: no
PSet_COBIE - NominalLength: 2000; NominalWidth: 100

# IfcWallStandardCase: Basic Wall:Basic Wall:28_WA_cb_G4/600_150, Basic Wall:Basic Wall:28_WA_cb_G4/600_150:6093
In: 00_begane grond
Type - PredefinedType: STANDARD; Material: 28_cellenbeton_G4/600 150 mm
Pset_WallCommon - Reference: Basic Wall:28_WA_cb_G4/600_150; LoadBearing: yes; ExtendToStructure: no; IsExternal: yes; ThermalTransmittance: 1.06667 kg/K/s3; Combustible: no; Compartmentation: no
PSet_COBIE - NominalLength: 2000; NominalWidth: 150

# IfcWallStandardCase: Basic Wall:Basic Wall:28_WA_ihwgb_C25_150, Basic Wall:Basic Wall:28_WA_ihwgb_C25_150:6092
In: 00_begane grond
Type - PredefinedType: STANDARD; Material: 28_beton_ihwg_C25_30 150 mm
Pset_WallCommon - Reference: Basic Wall:28_WA_ihwgb_C25_150; LoadBearing: yes; ExtendToStructure: no; IsExternal: yes; ThermalTransmittance: 6.97333 kg/K/s3; Combustible: no; Compartmentation: no
PSet_COBIE - NominalLength: 2000; NominalWidth: 150

# IfcWallStandardCase: Basic Wall:Basic Wall:28_WA_kzs-CS16_spouw_kzs-C16_330_150-30-150, Basic Wall:Basic Wall:28_WA_kzs-CS16_spouw_kzs-C16_330_150-30-150:5893
In: 00_begane grond
Type - PredefinedType: STANDARD; Material: 28_kalkzandsteen_CS16 150 mm, 00_lucht_spouw_muur_geventileerd 30 mm, 28_kalkzandsteen_CS16 150 mm
Pset_WallCommon - Reference: Basic Wall:28_WA_kzs-CS16_spouw_kzs-C16_330_150-30-150; LoadBearing: yes; ExtendToStructure: no; IsExternal: yes; ThermalTransmittance: 2.82536 kg/K/s3; Combustible: no; Compartmentation: no
PSet_COBIE - NominalLength: 2000; NominalWidth: 330

# IfcWallStandardCase: Basic Wall:Basic Wall:28_WA_kzs_CS16_100, Basic Wall:Basic Wall:28_WA_kzs_CS16_100:5889
In: 00_begane grond
Type - PredefinedType: STANDARD; Material: 28_kalkzandsteen_CS16 100 mm
Pset_WallCommon - Reference: Basic Wall:28_WA_kzs_CS16_100; LoadBearing: yes; ExtendToStructure: no; IsExternal: yes; ThermalTransmittance: 8.6 kg/K/s3; Combustible: no; Compartmentation: no
PSet_COBIE - NominalLength: 2000; NominalWidth: 100

# IfcWallStandardCase: Basic Wall:Basic Wall:28_WA_kzs_CS16_150, Basic Wall:Basic Wall:28_WA_kzs_CS16_150:5892
In: 00_begane grond
Type - PredefinedType: STANDARD; Material: 28_kalkzandsteen_CS16 150 mm
Pset_WallCommon - Reference: Basic Wall:28_WA_kzs_CS16_150; LoadBearing: yes; ExtendToStructure: no; IsExternal: yes; ThermalTransmittance: 5.73333 kg/K/s3; Combustible: no; Compartmentation: no
PSet_COBIE - NominalLength: 2000; NominalWidth: 150

# IfcWallStandardCase: Basic Wall:Basic Wall:28_WA_por_PM25_140, Basic Wall:Basic Wall:28_WA_por_PM25_140:5894
In: 00_begane grond
Type - PredefinedType: STANDARD; Material: 28_poriso_dragend 140 mm
Pset_WallCommon - Reference: Basic Wall:28_WA_por_PM25_140; LoadBearing: yes; ExtendToStructure: no; IsExternal: yes; ThermalTransmittance: 1.92857 kg/K/s3; Combustible: no; Compartmentation: no
PSet_COBIE - NominalLength: 2000; NominalWidth: 140

# IfcWallStandardCase: Basic Wall:Basic Wall:28_WA_prefabb_C45_150, Basic Wall:Basic Wall:28_WA_prefabb_C45_150:5896
In: 00_begane grond
Type - PredefinedType: STANDARD; Material: layer 150 mm
Pset_WallCommon - Reference: Basic Wall:28_WA_prefabb_C45_150; LoadBearing: yes; ExtendToStructure: no; IsExternal: yes; ThermalTransmittance: 6.97333 kg/K/s3; Combustible: no; Compartmentation: no
PSet_COBIE - NominalLength: 2000; NominalWidth: 150

# IfcWallStandardCase: Basic Wall:Basic Wall:42_WA_stucwerk_20 (2)
In: 00_begane grond
Type - PredefinedType: STANDARD; Material: 40_stucwerk_interieur_fijn_wit 20 mm
Pset_WallCommon - Reference: Basic Wall:42_WA_stucwerk_20; LoadBearing: no; ExtendToStructure: no; IsExternal: no; ThermalTransmittance: 25.5 kg/K/s3; Combustible: no; Compartmentation: no
PSet_COBIE - NominalLength: 2000; NominalWidth: 20
Name (Basic Wall:Basic Wall:42_WA_stucwerk_20:...)
5916
5919

# IfcWallStandardCase: Basic Wall:Basic Wall:42_WA_tegelwerk_150x150x10mm_op cementmortel_wit (2)
In: 00_begane grond
Type - PredefinedType: STANDARD; Material: 40_tegels_keramisch_150x150mm_wit 10 mm, 00_zandcement 20 mm
Pset_WallCommon - Reference: Basic Wall:42_WA_tegelwerk_150x150x10mm_op cementmortel_wit; LoadBearing: no; ExtendToStructure: no; IsExternal: no; ThermalTransmittance: 41.84 kg/K/s3; Combustible: no; Compartmentation: no
PSet_COBIE - NominalLength: 2000; NominalWidth: 30
Name (Basic Wall:Basic Wall:42_WA_tegelwerk_150x150x10mm_op cementmortel_wit:...)
5917
5918
